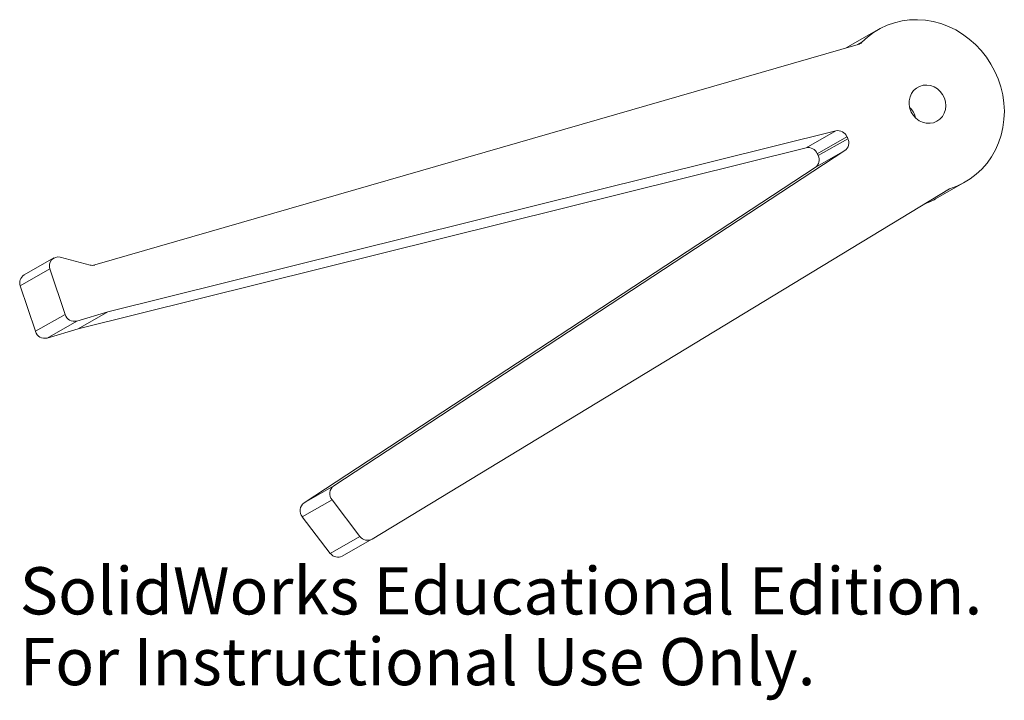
# Model space of a CAD drawing. Units: millimetres. Extents: x 20 to 121, y -36 to 34.
import ezdxf

# ---------------------------------------------------------------- set-up
doc = ezdxf.new("R2010")
doc.units = ezdxf.units.MM
doc.styles.add('SLDTEXTSTYLE0', font='TXT', dxfattribs={"width": 0.7})

msp = doc.modelspace()

# ---------------------------------------------------------------- linework, layer by layer
at = {"color": 7, "linetype": 'Continuous', "lineweight": 15}
for p, q in [((108.14, 32.65), (105.1, 30.91)), ((106.05, 31.11), (106.46, 31.35)), ((27.89, 8.54), (106.09, 31.12)), ((105.1, 30.91), (104.87, 30.77)), ((29.23, 3.74), (103.81, 22.28)), ((100.77, 20.54), (103.81, 22.28)), ((104.94, 21.68), (101.9, 19.94)), ((101.99, 19.74), (105.03, 21.47)), ((26.19, 2.01), (100.77, 20.54)), ((104.73, 20.26), (52.36, -14.09)), ((104.73, 20.26), (101.69, 18.52)), ((101.69, 18.52), (49.32, -15.83)), ((56.29, -19.54), (115.43, 16.35)), ((114.01, 15.31), (117.06, 17.04)), ((23.68, 9.26), (20.64, 7.52)), ((24.35, 9.34), (27.41, 8.53)), ((23.29, 8.13), (20.25, 6.39)), ((24.84, 3.48), (23.29, 8.13)), ((21.8, 1.75), (20.25, 6.39)), ((21.8, 1.75), (24.84, 3.48)), ((26.04, 2.8), (29.23, 3.74)), ((29.23, 3.74), (26.19, 2.01)), ((26.04, 2.8), (23, 1.06)), ((23, 1.06), (26.19, 2.01)), ((49.32, -15.83), (52.36, -14.09)), ((52.19, -15.51), (49.14, -17.24)), ((52.19, -15.51), (55.05, -19.26)), ((49.14, -17.24), (52.01, -20.99)), ((52.01, -20.99), (55.05, -19.26)), ((53.23, -21.28), (56.27, -19.55))]:
    msp.add_line(p, q, dxfattribs=at)
at = {"color": 7, "linetype": 'Continuous', "lineweight": 15, "flags": 128}
for points in [[(115.43, 16.35), (116.18, 16.61), (116.89, 16.95), (117.56, 17.36), (118.19, 17.83), (118.77, 18.37), (119.29, 18.97), (119.75, 19.62), (120.14, 20.32), (120.47, 21.05), (120.73, 21.83), (120.92, 22.63), (121.02, 23.45), (121.06, 24.28), (121.01, 25.12), (120.89, 25.95), (120.7, 26.78), (120.43, 27.59), (120.09, 28.37), (119.69, 29.12), (119.22, 29.83), (118.69, 30.5), (118.11, 31.12), (117.47, 31.68), (116.79, 32.17), (116.08, 32.61), (115.33, 32.97), (114.56, 33.26), (113.77, 33.47), (112.97, 33.6), (112.16, 33.66), (111.36, 33.64), (110.58, 33.53), (109.81, 33.35), (109.06, 33.09), (108.35, 32.76), (107.67, 32.36), (107.04, 31.88), (106.46, 31.35)], [(113.82, 23.11), (114.16, 23.26), (114.46, 23.47), (114.72, 23.75), (114.9, 24.08), (115.02, 24.45), (115.07, 24.84), (115.03, 25.24), (114.92, 25.62), (114.74, 25.99), (114.5, 26.31), (114.2, 26.58), (113.86, 26.78), (113.49, 26.91), (113.11, 26.96), (112.74, 26.94), (112.38, 26.83), (112.05, 26.65), (111.77, 26.4), (111.55, 26.1), (111.4, 25.75), (111.31, 25.36), (111.31, 24.97), (111.38, 24.57), (111.53, 24.2), (111.74, 23.85), (112.01, 23.56), (112.33, 23.32), (112.69, 23.15), (113.06, 23.06), (113.45, 23.05), (113.82, 23.11)]]:
    msp.add_lwpolyline(points, dxfattribs=at)
at = {"color": 7, "linetype": 'Continuous', "lineweight": 15}
for centre, radius, start, end in [((105.85, 31.94), 0.851, 286.0912, 315.6967), ((109.87, 23.11), 2.16, 12.9513, 46.5004), ((104.01, 21.3), 0.999, 22.0173, 101.8471), ((104.18, 21.04), 0.96, 305.3251, 26.8137), ((113.86, 25.57), 9.73, 203.5539, 204.8691), ((100.97, 19.57), 0.999, 22.0173, 101.8471), ((101.14, 19.31), 0.96, 305.3251, 26.8137), ((110.82, 23.83), 9.73, 203.5539, 204.8691), ((110.23, 21.94), 7.64, 289.5043, 299.7216), ((24.13, 8.46), 0.903, 75.9968, 201.939), ((27.64, 9.4), 0.899, 254.9651, 285.8546), ((21.13, 6.72), 0.938, 121.2778, 200.5825), ((25.8, 3.77), 1, 196.7725, 284.0329), ((22.76, 2.03), 1, 196.7725, 284.0329), ((52.94, -14.88), 0.981, 126.0101, 219.602), ((49.9, -16.62), 0.981, 126.0101, 219.602), ((55.82, -18.71), 0.947, 215.3236, 299.2082), ((52.79, -20.44), 0.949, 215.3596, 297.7587)]:
    msp.add_arc(centre, radius, start, end, dxfattribs=at)

# ---------------------------------------------------------------- texts
at = {"color": 7, "linetype": 'Continuous', "char_height": 4.8336, "attachment_point": 1, "style": 'SLDTEXTSTYLE0'}
for s, insert in [('SolidWorks Educational Edition.', (20.19, -22.41)), ('For Instructional Use Only.', (20.19, -29.66))]:
    msp.add_mtext(s, dxfattribs=dict(at, insert=insert))

doc.saveas('drawing.dxf')
